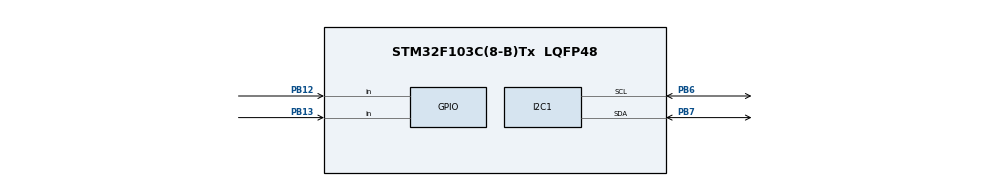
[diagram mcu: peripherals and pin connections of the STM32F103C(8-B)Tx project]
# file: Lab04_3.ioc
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Mcu.Family=STM32F1
Mcu.Name=STM32F103C(8-B)Tx
Mcu.Package=LQFP48
NVIC.PriorityGroup=NVIC_PRIORITYGROUP_4
PA13.Mode=Serial_Wire
PA13.Signal=SYS_JTMS-SWDIO
PA14.Mode=Serial_Wire
PA14.Signal=SYS_JTCK-SWCLK
PB12.GPIO_PuPd=GPIO_PULLDOWN
PB12.Signal=GPIO_Input
PB13.GPIO_PuPd=GPIO_PULLDOWN
PB13.Signal=GPIO_Input
PB6.Mode=I2C
PB6.Signal=I2C1_SCL
PB7.Mode=I2C
PB7.Signal=I2C1_SDA
PD0-OSC_IN.Mode=HSE-External-Oscillator
PD0-OSC_IN.Signal=RCC_OSC_IN
PD1-OSC_OUT.Mode=HSE-External-Oscillator
PD1-OSC_OUT.Signal=RCC_OSC_OUT
ProjectManager.HeapSize=0x200
ProjectManager.StackSize=0x400
ProjectManager.TargetToolchain=CMake
RCC.AHBFreq_Value=72000000
RCC.APB1CLKDivider=RCC_HCLK_DIV2
RCC.APB1Freq_Value=36000000
RCC.APB1TimFreq_Value=72000000
RCC.APB2Freq_Value=72000000
RCC.APB2TimFreq_Value=72000000
RCC.HCLKFreq_Value=72000000
RCC.PLLMUL=RCC_PLL_MUL9
RCC.PLLSourceVirtual=RCC_PLLSOURCE_HSE
RCC.SYSCLKFreq_VALUE=72000000
RCC.SYSCLKSource=RCC_SYSCLKSOURCE_PLLCLK
RCC.USBFreq_Value=72000000
board=custom

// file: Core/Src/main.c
/* USER CODE BEGIN Header */
/**
  ******************************************************************************
  * @file           : main.c
  * @brief          : Main program body
  ******************************************************************************
  * @attention
  *
  * Copyright (c) 2026 STMicroelectronics.
  * All rights reserved.
  *
  * This software is licensed under terms that can be found in the LICENSE file
  * in the root directory of this software component.
  * If no LICENSE file comes with this software, it is provided AS-IS.
  *
  ******************************************************************************
  */
/* USER CODE END Header */
#include "main.h"

/* USER CODE BEGIN Includes */
#include "i2c-lcd.h"
#include <stdio.h>
/* USER CODE END Includes */

I2C_HandleTypeDef hi2c1;

void SystemClock_Config(void);
static void MX_GPIO_Init(void);
static void MX_I2C1_Init(void);
/* USER CODE BEGIN PFP */
void update_lcd_display(int pos);
/* USER CODE END PFP */

/* USER CODE BEGIN 0 */
// ฟังก์ชันช่วยอัปเดตการแสดงผลบนจอ LCD
void update_lcd_display(int pos)
{
  char lcd_buffer[20];

  lcd_clear();

  // บรรทัดแรก: แสดงตัว # ณ ตำแหน่ง pos (0 ถึง 15)
  lcd_put_cur(0, pos);
  lcd_send_string("#");

  // บรรทัดสอง: แสดงค่าตำแหน่ง เช่น "Position : 0"
  snprintf(lcd_buffer, sizeof(lcd_buffer), "Position : %-2d", pos);
  lcd_put_cur(1, 0);
  lcd_send_string(lcd_buffer);
}
/* USER CODE END 0 */

int main(void)
{

  /* USER CODE BEGIN 1 */
  int pos = 0; // ตำแหน่งของ # (เริ่มต้นที่ซ้ายสุดคือ 0)
  /* USER CODE END 1 */

  /* MCU Configuration--------------------------------------------------------*/

  /* Reset of all peripherals, Initializes the Flash interface and the Systick. */
  HAL_Init();

  /* Configure the system clock */
  SystemClock_Config();

  /* Initialize all configured peripherals */
  MX_GPIO_Init();
  MX_I2C1_Init();

  /* USER CODE BEGIN 2 */
  lcd_init();               // เริ่มการทำงานของจอ LCD
  update_lcd_display(pos);  // แสดงผลเริ่มต้น (ตำแหน่ง 0)
  /* USER CODE END 2 */

  /* Infinite loop */
  while (1)
  {

    /* USER CODE BEGIN 3 */
    // --- ตรวจสอบการกดปุ่ม 1 (PA0: เลื่อนขวา) ---
    if (HAL_GPIO_ReadPin(GPIOA, GPIO_PIN_0) == GPIO_PIN_RESET)
    {
      if (pos < 15) // ถ้ายังไม่ถึงขวาสุด (ขวาสุดคือ 15)
      {
        pos++;      // เลื่อนตำแหน่งไปทางขวา 1 ช่อง
        update_lcd_display(pos);
      }
      HAL_Delay(200); // หน่วงเวลาป้องกันสัญญาณปุ่มเด้งเบิ้ล (Debounce)
    }

    // --- ตรวจสอบการกดปุ่ม 2 (PA1: เลื่อนซ้าย) ---
    if (HAL_GPIO_ReadPin(GPIOA, GPIO_PIN_1) == GPIO_PIN_RESET)
    {
      if (pos > 0)  // ถ้ายังไม่ถึงซ้ายสุด (ซ้ายสุดคือ 0)
      {
        pos--;      // เลื่อนตำแหน่งไปทางซ้าย 1 ช่อง
        update_lcd_display(pos);
      }
      HAL_Delay(200); // หน่วงเวลาป้องกันสัญญาณปุ่มเด้งเบิ้ล (Debounce)
    }
  }
  /* USER CODE END 3 */
}

void SystemClock_Config(void)
{
  RCC_OscInitTypeDef RCC_OscInitStruct = {0};
  RCC_ClkInitTypeDef RCC_ClkInitStruct = {0};

  /** Initializes the RCC Oscillators according to the specified parameters
  * in the RCC_OscInitTypeDef structure.
  */
  RCC_OscInitStruct.OscillatorType = RCC_OSCILLATORTYPE_HSI;
  RCC_OscInitStruct.HSIState = RCC_HSI_ON;
  RCC_OscInitStruct.HSICalibrationValue = RCC_HSICALIBRATION_DEFAULT;
  RCC_OscInitStruct.PLL.PLLState = RCC_PLL_NONE;
  if (HAL_RCC_OscConfig(&RCC_OscInitStruct) != HAL_OK)
  {
    Error_Handler();
  }

  /** Initializes the CPU, AHB and APB buses clocks
  */
  RCC_ClkInitStruct.ClockType = RCC_CLOCKTYPE_HCLK|RCC_CLOCKTYPE_SYSCLK
                              |RCC_CLOCKTYPE_PCLK1|RCC_CLOCKTYPE_PCLK2;
  RCC_ClkInitStruct.SYSCLKSource = RCC_SYSCLKSOURCE_HSI;
  RCC_ClkInitStruct.AHBCLKDivider = RCC_SYSCLK_DIV1;
  RCC_ClkInitStruct.APB1CLKDivider = RCC_HCLK_DIV1;
  RCC_ClkInitStruct.APB2CLKDivider = RCC_HCLK_DIV1;

  if (HAL_RCC_ClockConfig(&RCC_ClkInitStruct, FLASH_LATENCY_0) != HAL_OK)
  {
    Error_Handler();
  }
}

static void MX_I2C1_Init(void)
{

  hi2c1.Instance = I2C1;
  hi2c1.Init.ClockSpeed = 100000;
  hi2c1.Init.DutyCycle = I2C_DUTYCYCLE_2;
  hi2c1.Init.OwnAddress1 = 0;
  hi2c1.Init.AddressingMode = I2C_ADDRESSINGMODE_7BIT;
  hi2c1.Init.DualAddressMode = I2C_DUALADDRESS_DISABLE;
  hi2c1.Init.OwnAddress2 = 0;
  hi2c1.Init.GeneralCallMode = I2C_GENERALCALL_DISABLE;
  hi2c1.Init.NoStretchMode = I2C_NOSTRETCH_DISABLE;
  if (HAL_I2C_Init(&hi2c1) != HAL_OK)
  {
    Error_Handler();
  }

}

static void MX_GPIO_Init(void)
{
  GPIO_InitTypeDef GPIO_InitStruct = {0};

  /* GPIO Ports Clock Enable */
  __HAL_RCC_GPIOA_CLK_ENABLE();
  __HAL_RCC_GPIOB_CLK_ENABLE();

  /* ตั้งค่า PA0 (ปุ่ม 1 - เลื่อนขวา) และ PA1 (ปุ่ม 2 - เลื่อนซ้าย) เป็น Input แบบ Pull-Up */
  GPIO_InitStruct.Pin = GPIO_PIN_0 | GPIO_PIN_1;
  GPIO_InitStruct.Mode = GPIO_MODE_INPUT;
  GPIO_InitStruct.Pull = GPIO_PULLUP;
  HAL_GPIO_Init(GPIOA, &GPIO_InitStruct);
}

void Error_Handler(void)
{
  __disable_irq();
  while (1)
  {
  }
}
